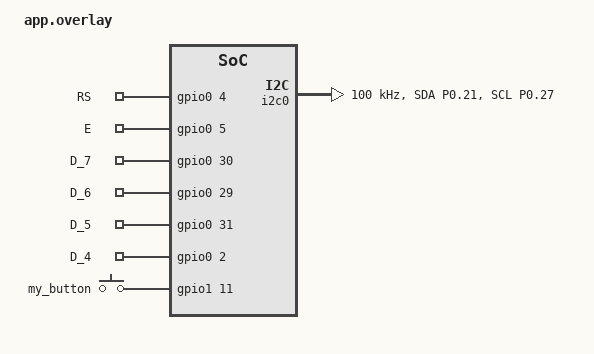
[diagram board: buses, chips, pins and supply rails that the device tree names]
/ {
    aliases {
        d-7 = &D_7;
        d-6 = &D_6;
        d-5 = &D_5;
        d-4 = &D_4;
        rs = &RS;
        e = &E;
        my-button = &my_button;
    };

    keypad_pins {
        compatible = "gpio-keys";
        RS: RS {
            gpios = <&gpio0 4 (GPIO_ACTIVE_HIGH | GPIO_PULL_UP)>;
        };
        E: E {
            gpios = <&gpio0 5 (GPIO_ACTIVE_HIGH | GPIO_PULL_UP)>;
        };
        D_7: D_7 {
            gpios = <&gpio0 30 (GPIO_ACTIVE_HIGH | GPIO_PULL_UP)>;
        };
        D_6: D_6 {
            gpios = <&gpio0 29 (GPIO_ACTIVE_HIGH | GPIO_PULL_UP)>;
        };
        D_5: D_5 {
            gpios = <&gpio0 31 (GPIO_ACTIVE_HIGH | GPIO_PULL_UP)>;
        };
        D_4: D_4 {
            gpios = <&gpio0 2 (GPIO_ACTIVE_HIGH | GPIO_PULL_UP)>;
        };
        my_button: my_button {
            gpios = <&gpio1 11 (GPIO_ACTIVE_HIGH)>;
        };
    };
};

&pinctrl {
    i2c0_default_custom: i2c0_default_custom {
        group1 {
            psels = <NRF_PSEL(TWIM_SDA, 0, 21)>,
                    <NRF_PSEL(TWIM_SCL, 0, 27)>;
            bias-pull-up;
        };
    };

    i2c0_sleep_custom: i2c0_sleep_custom {
        group1 {
            psels = <NRF_PSEL(TWIM_SDA, 0, 21)>,
                    <NRF_PSEL(TWIM_SCL, 0, 27)>;
            low-power-enable;
        };
    };
};

&i2c0 {
    status = "okay";
    pinctrl-0 = <&i2c0_default_custom>;
    pinctrl-1 = <&i2c0_sleep_custom>;
    pinctrl-names = "default", "sleep";
    clock-frequency = <I2C_BITRATE_STANDARD>;
};
